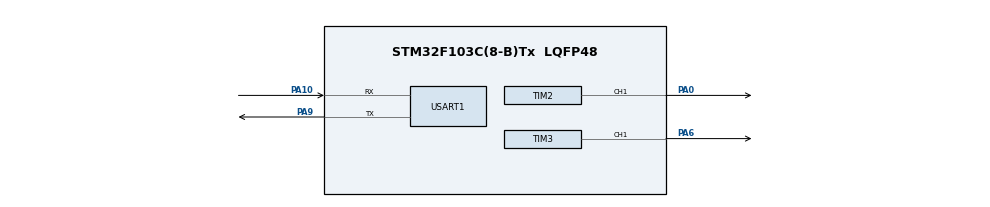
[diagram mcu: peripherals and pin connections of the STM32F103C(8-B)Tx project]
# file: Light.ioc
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Dma.Request0=TIM2_CH1
Dma.TIM2_CH1.0.Direction=DMA_MEMORY_TO_PERIPH
Dma.TIM2_CH1.0.Instance=DMA1_Channel5
Dma.TIM2_CH1.0.MemDataAlignment=DMA_MDATAALIGN_HALFWORD
Dma.TIM2_CH1.0.MemInc=DMA_MINC_ENABLE
Dma.TIM2_CH1.0.Mode=DMA_CIRCULAR
Dma.TIM2_CH1.0.PeriphDataAlignment=DMA_PDATAALIGN_HALFWORD
Dma.TIM2_CH1.0.PeriphInc=DMA_PINC_DISABLE
Dma.TIM2_CH1.0.Priority=DMA_PRIORITY_VERY_HIGH
Mcu.Family=STM32F1
Mcu.Name=STM32F103C(8-B)Tx
Mcu.Package=LQFP48
NVIC.DMA1_Channel5_IRQn=true\:0\:0\:false\:false\:true\:false\:true\:true
NVIC.PriorityGroup=NVIC_PRIORITYGROUP_4
NVIC.TIM2_IRQn=true\:0\:0\:false\:false\:true\:true\:true\:true
NVIC.TIM3_IRQn=true\:0\:0\:false\:false\:true\:true\:true\:true
PA0-WKUP.Signal=S_TIM2_CH1_ETR
PA10.Mode=Asynchronous
PA10.Signal=USART1_RX
PA13.Mode=Serial_Wire
PA13.Signal=SYS_JTMS-SWDIO
PA14.Mode=Serial_Wire
PA14.Signal=SYS_JTCK-SWCLK
PA6.Signal=S_TIM3_CH1
PA9.Mode=Asynchronous
PA9.Signal=USART1_TX
PD0-OSC_IN.Mode=HSE-External-Oscillator
PD0-OSC_IN.Signal=RCC_OSC_IN
PD1-OSC_OUT.Mode=HSE-External-Oscillator
PD1-OSC_OUT.Signal=RCC_OSC_OUT
ProjectManager.HeapSize=0x200
ProjectManager.StackSize=0x400
ProjectManager.TargetToolchain=CMake
RCC.APB1Freq_Value=8000000
RCC.APB2Freq_Value=8000000
SH.S_TIM2_CH1_ETR.0=TIM2_CH1,PWM Generation1 CH1
SH.S_TIM3_CH1.0=TIM3_CH1,PWM Generation1 CH1
TIM2.AutoReloadPreload=TIM_AUTORELOAD_PRELOAD_ENABLE
TIM2.Channel-PWM\ Generation1\ CH1=TIM_CHANNEL_1
TIM2.Period=89
TIM3.AutoReloadPreload=TIM_AUTORELOAD_PRELOAD_ENABLE
TIM3.Channel-PWM\ Generation1\ CH1=TIM_CHANNEL_1
TIM3.Period=499
TIM3.Prescaler=71
USART1.VirtualMode=VM_ASYNC
VP_TIM2_VS_ClockSourceINT.Mode=Internal
VP_TIM3_VS_ClockSourceINT.Mode=Internal
board=custom

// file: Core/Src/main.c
/* USER CODE BEGIN Header */
/**
  ******************************************************************************
  * @file           : main.c
  * @brief          : Main program body
  ******************************************************************************
  * @attention
  *
  * Copyright (c) 2026 STMicroelectronics.
  * All rights reserved.
  *
  * This software is licensed under terms that can be found in the LICENSE file
  * in the root directory of this software component.
  * If no LICENSE file comes with this software, it is provided AS-IS.
  *
  ******************************************************************************
  */
/* USER CODE END Header */
#include "main.h"
#include "dma.h"
#include "tim.h"
#include "usart.h"
#include "gpio.h"

/* USER CODE BEGIN Includes */
#include "ws2812b.h"
#include "buzzer.h"
#include "uart_protocol.h"
#include "fatigue_feedback.h"
/* USER CODE END Includes */

void SystemClock_Config(void);

int main(void)
{

  /* MCU Configuration--------------------------------------------------------*/

  /* Reset of all peripherals, Initializes the Flash interface and the Systick. */
  HAL_Init();

  /* Configure the system clock */
  SystemClock_Config();

  /* Initialize all configured peripherals */
  MX_GPIO_Init();
  MX_DMA_Init();
  MX_TIM2_Init();
  MX_USART1_UART_Init();
  MX_TIM3_Init();
  /* USER CODE BEGIN 2 */
  WS2812B_Init(&htim2, TIM_CHANNEL_1);
  Buzzer_Init(&htim3, TIM_CHANNEL_1);
  UART_Protocol_Init(&huart1);
  Feedback_Init();
  /* USER CODE END 2 */

  /* Infinite loop */
  while (1)
  {

    /* USER CODE BEGIN 3 */
    uint32_t now = HAL_GetTick();
    FatiguePacket pkt = UART_Protocol_Parse();
    if (pkt.valid) {
      Feedback_SetLevel((FatigueLevel)pkt.level);
    }
    Feedback_Tick(now);
  }
  /* USER CODE END 3 */
}

void SystemClock_Config(void)
{
  RCC_OscInitTypeDef RCC_OscInitStruct = {0};
  RCC_ClkInitTypeDef RCC_ClkInitStruct = {0};

  /** Initializes the RCC Oscillators according to the specified parameters
  * in the RCC_OscInitTypeDef structure.
  */
  /* HSE 8MHz + PLL x9 = 72MHz */
  RCC_OscInitStruct.OscillatorType = RCC_OSCILLATORTYPE_HSE;
  RCC_OscInitStruct.HSEState = RCC_HSE_ON;
  RCC_OscInitStruct.HSEPredivValue = RCC_HSE_PREDIV_DIV1;
  RCC_OscInitStruct.PLL.PLLState = RCC_PLL_ON;
  RCC_OscInitStruct.PLL.PLLSource = RCC_PLLSOURCE_HSE;
  RCC_OscInitStruct.PLL.PLLMUL = RCC_PLL_MUL9;
  if (HAL_RCC_OscConfig(&RCC_OscInitStruct) != HAL_OK)
  {
    Error_Handler();
  }

  /** Initializes the CPU, AHB and APB buses clocks
  */
  RCC_ClkInitStruct.ClockType = RCC_CLOCKTYPE_HCLK|RCC_CLOCKTYPE_SYSCLK
                              |RCC_CLOCKTYPE_PCLK1|RCC_CLOCKTYPE_PCLK2;
  RCC_ClkInitStruct.SYSCLKSource = RCC_SYSCLKSOURCE_PLLCLK;
  RCC_ClkInitStruct.AHBCLKDivider = RCC_SYSCLK_DIV1;
  RCC_ClkInitStruct.APB1CLKDivider = RCC_HCLK_DIV2;   /* APB1 = 36MHz */
  RCC_ClkInitStruct.APB2CLKDivider = RCC_HCLK_DIV1;   /* APB2 = 72MHz */

  if (HAL_RCC_ClockConfig(&RCC_ClkInitStruct, FLASH_LATENCY_2) != HAL_OK)
  {
    Error_Handler();
  }
}

/* USER CODE BEGIN 4 */
void HAL_TIM_PWM_PulseFinishedCallback(TIM_HandleTypeDef *htim)
{
  if (htim->Instance == TIM2) {
    WS2812B_DMA_Callback();
  }
}
/* USER CODE END 4 */

void Error_Handler(void)
{
  __disable_irq();
  while (1)
  {
  }
}
